VERSION 5.8 ;
BUSBITCHARS "[]" ;
DIVIDERCHAR "/" ;
UNITS
    DATABASE MICRONS 1000 ;
END UNITS

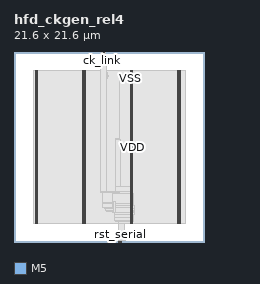
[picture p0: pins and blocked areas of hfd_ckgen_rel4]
MACRO hfd_ckgen_rel4
  FOREIGN hfd_ckgen_rel4 0 0 ;
  CLASS BLOCK ;
  SIZE 21.6 BY 21.6 ;
  PIN ck_hbm
    DIRECTION INPUT ;
    USE SIGNAL ;
    PORT
      LAYER M5 ;
        RECT  9.936 21.516 9.96 21.6 ;
    END
  END ck_hbm
  PIN ck_link
    DIRECTION INPUT ;
    USE SIGNAL ;
    PORT
      LAYER M5 ;
        RECT  10.032 21.516 10.056 21.6 ;
    END
  END ck_link
  PIN ck_serial
    DIRECTION INPUT ;
    USE SIGNAL ;
    PORT
      LAYER M5 ;
        RECT  10.128 21.516 10.152 21.6 ;
    END
  END ck_serial
  PIN ck_stream
    DIRECTION INPUT ;
    USE SIGNAL ;
    PORT
      LAYER M5 ;
        RECT  10.224 21.516 10.248 21.6 ;
    END
  END ck_stream
  PIN locked
    DIRECTION INPUT ;
    USE SIGNAL ;
    PORT
      LAYER M5 ;
        RECT  10.32 21.516 10.344 21.6 ;
    END
  END locked
  PIN por_n
    DIRECTION INPUT ;
    USE SIGNAL ;
    PORT
      LAYER M5 ;
        RECT  10.416 21.516 10.44 21.6 ;
    END
  END por_n
  PIN rst_hbm
    DIRECTION OUTPUT ;
    USE SIGNAL ;
    PORT
      LAYER M5 ;
        RECT  11.856 0 11.88 0.084 ;
    END
  END rst_hbm
  PIN rst_link
    DIRECTION OUTPUT ;
    USE SIGNAL ;
    PORT
      LAYER M5 ;
        RECT  11.952 0 11.976 0.084 ;
    END
  END rst_link
  PIN rst_serial
    DIRECTION OUTPUT ;
    USE SIGNAL ;
    PORT
      LAYER M5 ;
        RECT  12.048 0 12.072 0.084 ;
    END
  END rst_serial
  PIN rst_stream
    DIRECTION OUTPUT ;
    USE SIGNAL ;
    PORT
      LAYER M5 ;
        RECT  12.144 0 12.168 0.084 ;
    END
  END rst_stream
  PIN VDD
    DIRECTION INOUT ;
    USE POWER ;
    PORT
      LAYER M5 ;
        RECT  18.792 2.151 18.912 19.449 ;
        RECT  13.392 2.151 13.512 19.449 ;
        RECT  7.992 2.151 8.112 19.449 ;
        RECT  2.592 2.151 2.712 19.449 ;
    END
  END VDD
  PIN VSS
    DIRECTION INOUT ;
    USE GROUND ;
    PORT
      LAYER M5 ;
        RECT  18.6 2.137 18.72 19.463 ;
        RECT  13.2 2.137 13.32 19.463 ;
        RECT  7.8 2.137 7.92 19.463 ;
        RECT  2.4 2.137 2.52 19.463 ;
    END
  END VSS
  # OT_OBS_CLOSED layer=M5 d_um=1.536 added=2
  OBS
    LAYER RVTN ;
     RECT  2.16 2.16 19.44 2.295 ;
     RECT  2.16 2.565 19.44 2.835 ;
     RECT  2.16 3.105 19.44 3.375 ;
     RECT  2.16 3.645 19.44 3.915 ;
     RECT  2.16 4.185 19.44 4.455 ;
     RECT  2.16 4.725 19.44 4.995 ;
     RECT  2.16 5.265 19.44 5.535 ;
     RECT  2.16 5.805 19.44 6.075 ;
     RECT  2.16 6.345 19.44 6.615 ;
     RECT  2.16 6.885 19.44 7.155 ;
     RECT  2.16 7.425 19.44 7.695 ;
     RECT  2.16 7.965 19.44 8.235 ;
     RECT  2.16 8.505 19.44 8.775 ;
     RECT  2.16 9.045 19.44 9.315 ;
     RECT  2.16 9.585 19.44 9.855 ;
     RECT  2.16 10.125 19.44 10.395 ;
     RECT  2.16 10.665 19.44 10.935 ;
     RECT  2.16 11.205 19.44 11.475 ;
     RECT  2.16 11.745 19.44 12.015 ;
     RECT  2.16 12.285 19.44 12.555 ;
     RECT  2.16 12.825 19.44 13.095 ;
     RECT  2.16 13.365 19.44 13.635 ;
     RECT  2.16 13.905 19.44 14.175 ;
     RECT  2.16 14.445 19.44 14.715 ;
     RECT  2.16 14.985 19.44 15.255 ;
     RECT  2.16 15.525 19.44 15.795 ;
     RECT  2.16 16.065 19.44 16.335 ;
     RECT  2.16 16.605 19.44 16.875 ;
     RECT  2.16 17.145 19.44 17.415 ;
     RECT  2.16 17.685 19.44 17.955 ;
     RECT  2.16 18.225 19.44 18.495 ;
     RECT  2.16 18.765 19.44 19.035 ;
     RECT  2.16 19.305 19.44 19.44 ;
    LAYER RVTP ;
     RECT  2.16 2.295 19.44 2.565 ;
     RECT  2.16 2.835 19.44 3.105 ;
     RECT  2.16 3.375 19.44 3.645 ;
     RECT  2.16 3.915 19.44 4.185 ;
     RECT  2.16 4.455 19.44 4.725 ;
     RECT  2.16 4.995 19.44 5.265 ;
     RECT  2.16 5.535 19.44 5.805 ;
     RECT  2.16 6.075 19.44 6.345 ;
     RECT  2.16 6.615 19.44 6.885 ;
     RECT  2.16 7.155 19.44 7.425 ;
     RECT  2.16 7.695 19.44 7.965 ;
     RECT  2.16 8.235 19.44 8.505 ;
     RECT  2.16 8.775 19.44 9.045 ;
     RECT  2.16 9.315 19.44 9.585 ;
     RECT  2.16 9.855 19.44 10.125 ;
     RECT  2.16 10.395 19.44 10.665 ;
     RECT  2.16 10.935 19.44 11.205 ;
     RECT  2.16 11.475 19.44 11.745 ;
     RECT  2.16 12.015 19.44 12.285 ;
     RECT  2.16 12.555 19.44 12.825 ;
     RECT  2.16 13.095 19.44 13.365 ;
     RECT  2.16 13.635 19.44 13.905 ;
     RECT  2.16 14.175 19.44 14.445 ;
     RECT  2.16 14.715 19.44 14.985 ;
     RECT  2.16 15.255 19.44 15.525 ;
     RECT  2.16 15.795 19.44 16.065 ;
     RECT  2.16 16.335 19.44 16.605 ;
     RECT  2.16 16.875 19.44 17.145 ;
     RECT  2.16 17.415 19.44 17.685 ;
     RECT  2.16 17.955 19.44 18.225 ;
     RECT  2.16 18.495 19.44 18.765 ;
     RECT  2.16 19.035 19.44 19.305 ;
    LAYER M1 ;
     RECT  2.16 2.151 19.44 19.449 ;
    LAYER M2 ;
     RECT  2.16 2.151 19.44 19.449 ;
    LAYER M3 ;
     RECT  11.844 0.091 12.222 0.139 ;
     RECT  11.844 0.139 12.618 2.143 ;
     RECT  11.844 2.143 13.305 2.371 ;
     RECT  2.415 2.143 2.505 2.413 ;
     RECT  7.815 2.143 7.905 2.413 ;
     RECT  18.615 2.143 18.705 2.413 ;
     RECT  11.556 2.371 13.59 2.497 ;
     RECT  11.376 2.497 13.59 2.803 ;
     RECT  11.376 2.803 13.626 3.109 ;
     RECT  11.376 3.109 13.698 3.307 ;
     RECT  11.16 3.307 13.698 3.451 ;
     RECT  10.512 3.451 13.698 3.577 ;
     RECT  10.404 3.577 13.698 3.835 ;
     RECT  10.332 3.835 13.698 4.109 ;
     RECT  10.332 4.109 13.626 4.415 ;
     RECT  10.584 4.415 13.626 5.459 ;
     RECT  10.584 5.459 13.497 5.729 ;
     RECT  11.304 5.729 13.497 5.765 ;
     RECT  11.52 5.765 13.497 6.269 ;
     RECT  11.52 6.269 12.15 11.669 ;
     RECT  11.52 11.669 11.97 11.813 ;
     RECT  10.44 18.535 10.458 18.571 ;
     RECT  10.44 18.571 10.602 18.841 ;
     RECT  10.44 18.841 10.782 18.959 ;
     RECT  11.952 11.813 11.97 18.959 ;
     RECT  10.44 18.959 10.674 19.075 ;
     RECT  2.415 2.413 2.697 19.187 ;
     RECT  7.815 2.413 8.097 19.187 ;
     RECT  13.215 6.269 13.497 19.187 ;
     RECT  18.615 2.413 18.897 19.187 ;
     RECT  10.296 19.075 10.674 19.229 ;
     RECT  10.296 19.229 10.494 19.265 ;
     RECT  10.296 19.265 10.458 19.325 ;
     RECT  10.296 19.325 10.314 19.373 ;
     RECT  2.415 19.187 2.505 19.457 ;
     RECT  7.815 19.187 7.905 19.457 ;
     RECT  13.215 19.187 13.305 19.457 ;
     RECT  18.615 19.187 18.705 19.457 ;
     RECT  10.152 21.067 10.17 21.259 ;
     RECT  10.152 21.259 10.242 21.389 ;
     RECT  10.224 21.389 10.242 21.485 ;
    LAYER M4 ;
     RECT  2.408 2.148 2.512 19.452 ;
     RECT  2.512 2.418 2.704 19.182 ;
     RECT  7.808 2.148 7.912 19.452 ;
     RECT  7.912 2.418 8.104 19.182 ;
     RECT  9.781 21.168 10.124 21.384 ;
     RECT  10.021 3.936 10.165 3.96 ;
     RECT  10.124 21.072 10.211 21.384 ;
     RECT  10.211 21.168 10.213 21.384 ;
     RECT  10.213 21.168 10.297 21.48 ;
     RECT  10.165 3.936 10.321 4.44 ;
     RECT  10.285 19.344 10.368 19.368 ;
     RECT  10.368 19.296 10.369 19.368 ;
     RECT  10.369 19.296 10.469 19.32 ;
     RECT  10.321 3.84 10.501 4.44 ;
     RECT  10.297 21.168 10.547 21.192 ;
     RECT  10.501 3.84 10.753 4.536 ;
     RECT  9.877 5.616 11.173 5.64 ;
     RECT  10.753 3.84 11.365 4.632 ;
     RECT  11.365 3.408 11.513 4.632 ;
     RECT  11.833 0.096 11.916 0.12 ;
     RECT  11.173 5.616 11.945 5.784 ;
     RECT  11.916 0.096 12.233 0.168 ;
     RECT  12.233 0.144 12.629 0.168 ;
     RECT  11.513 3.408 13.208 3.96 ;
     RECT  13.208 2.148 13.312 19.452 ;
     RECT  13.312 2.418 13.504 19.182 ;
     RECT  18.608 2.148 18.712 19.452 ;
     RECT  18.712 2.418 18.904 19.182 ;
    LAYER M5 ;
     RECT  11.88 0.016 11.952 0.084 ;
     RECT  11.976 0.016 12.048 0.084 ;
     RECT  12.072 0.016 12.144 0.084 ;
     RECT  11.856 0.084 12.168 0.131 ;
     RECT  11.952 0.131 12.168 0.179 ;
     RECT  2.4 2.137 2.52 2.151 ;
     RECT  7.8 2.137 7.92 2.151 ;
     RECT  13.2 2.137 13.32 2.151 ;
     RECT  18.6 2.137 18.72 2.151 ;
     RECT  10.032 3.925 10.056 4.405 ;
     RECT  10.032 4.405 10.2 4.501 ;
     RECT  11.184 3.829 11.208 4.501 ;
     RECT  10.032 4.501 11.208 5.605 ;
     RECT  9.888 5.605 11.208 5.795 ;
     RECT  2.4 2.151 2.712 19.449 ;
     RECT  7.8 2.151 8.112 19.449 ;
     RECT  13.2 2.151 13.512 19.449 ;
     RECT  18.6 2.151 18.912 19.449 ;
     RECT  2.4 19.449 2.52 19.463 ;
     RECT  7.8 19.449 7.92 19.463 ;
     RECT  13.2 19.449 13.32 19.463 ;
     RECT  18.6 19.449 18.72 19.463 ;
     RECT  9.888 5.795 10.536 21.157 ;
     RECT  9.792 21.157 10.536 21.203 ;
     RECT  9.792 21.203 10.44 21.395 ;
     RECT  9.936 21.395 10.44 21.516 ;
     RECT  9.96 21.516 10.032 21.584 ;
     RECT  10.056 21.516 10.128 21.584 ;
     RECT  10.152 21.516 10.224 21.584 ;
     RECT  10.248 21.516 10.32 21.584 ;
     RECT  10.344 21.516 10.416 21.584 ;
     RECT  10.056 3.925 11.184 4.405 ;
     RECT  10.2 4.405 11.184 4.501 ;
  END
END hfd_ckgen_rel4
END LIBRARY
